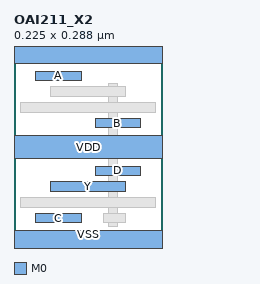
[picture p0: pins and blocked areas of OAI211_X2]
MACRO OAI211_X2
  CLASS CORE ;
  ORIGIN 0 0 ;
  FOREIGN OAI211_X2 0 0 ;
  SIZE 0.2250 BY 0.2880 ;
  SYMMETRY X Y ;
  SITE coresite ;
  PIN A
    DIRECTION INPUT ;
    USE SIGNAL ;
    PORT
      LAYER M0 ;
        RECT 0.0330 0.2450 0.1020 0.2590 ;
    END
  END A
  PIN B
    DIRECTION INPUT ;
    USE SIGNAL ;
    PORT
      LAYER M0 ;
        RECT 0.1230 0.1730 0.1920 0.1870 ;
    END
  END B
  PIN C
    DIRECTION INPUT ;
    USE SIGNAL ;
    PORT
      LAYER M0 ;
        RECT 0.0330 0.0290 0.1020 0.0430 ;
    END
  END C
  PIN D
    DIRECTION INPUT ;
    USE SIGNAL ;
    PORT
      LAYER M0 ;
        RECT 0.1230 0.1010 0.1920 0.1150 ;
    END
  END D
  PIN Y
    DIRECTION OUTPUT ;
    USE SIGNAL ;
    PORT
      LAYER M0 ;
        RECT 0.0555 0.0770 0.1695 0.0910 ;
    END
  END Y
  PIN VDD
    DIRECTION INOUT ;
    USE POWER ;
    SHAPE ABUTMENT ;
    PORT
      LAYER M0 ;
        RECT 0.0000 0.1260 0.2250 0.1620 ;
    END
  END VDD
  PIN VSS
    DIRECTION INOUT ;
    USE GROUND ;
    SHAPE ABUTMENT ;
    PORT
      LAYER M0 ;
        RECT 0.0000 -0.0180 0.2250 0.0180 ;
        RECT 0.0000 0.2700 0.2250 0.3060 ;
    END
  END VSS
  OBS
    LAYER V0 ;
      RECT 0.1430 0.0290 0.1570 0.0430 ;
      RECT 0.1430 0.2210 0.1570 0.2350 ;
    LAYER M1 ;
      RECT 0.1425 0.0240 0.1575 0.2400 ;
    LAYER M0 ;
      RECT 0.1350 0.0290 0.1695 0.0430 ;
      RECT 0.0105 0.0530 0.2145 0.0670 ;
      RECT 0.0105 0.1970 0.2145 0.2110 ;
      RECT 0.0555 0.2210 0.1695 0.2350 ;
  END
END OAI211_X2
